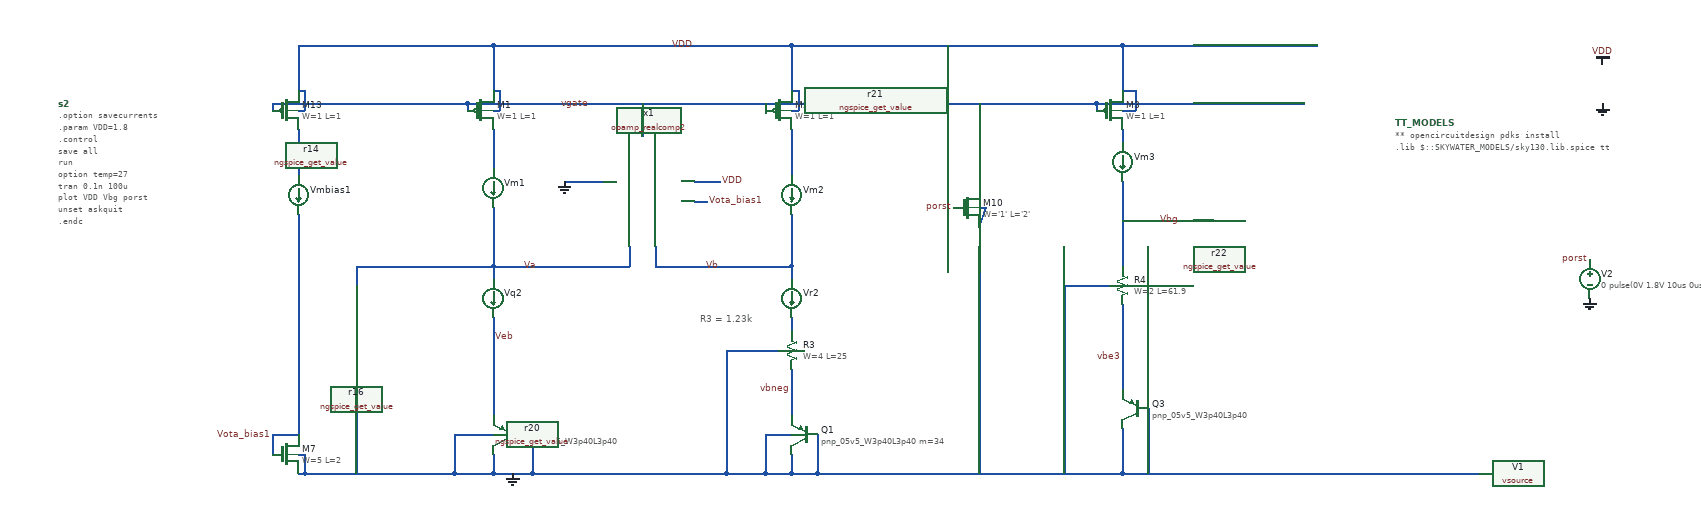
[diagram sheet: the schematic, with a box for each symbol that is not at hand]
v {xschem version=3.0.0 file_version=1.2 }
G {}
K {}
V {}
S {}
E {}
T {R3 = 1.23k} -650 -260 0 0 0.4 0.4 {}
N -970 -40 -970 -10 { lab=GND}
N -1030 -70 -970 -70 { lab=GND}
N -1030 -70 -1030 -10 { lab=GND}
N -970 -670 -750 -670 { lab=VDD}
N -510 -670 -310 -670 { lab=VDD}
N -510 -330 -510 -310 { lab=Vb}
N -510 -410 -510 -330 { lab=Vb}
N 0 -460 0 -330 { lab=Vbg}
N -510 -250 -510 -230 { lab=#net1}
N -510 -540 -510 -470 { lab=#net2}
N -510 -170 -510 -100 { lab=vbneg}
N -470 -70 -470 -10 { lab=GND}
N -510 -40 -510 -10 { lab=GND}
N -550 -70 -510 -70 { lab=GND}
N -550 -70 -550 -10 { lab=GND}
N -930 -70 -910 -70 { lab=GND}
N -910 -70 -910 -10 { lab=GND}
N -610 -200 -530 -200 { lab=GND}
N -610 -200 -610 -10 { lab=GND}
N -970 -250 -970 -100 { lab=Veb}
N -620 -330 -510 -330 { lab=Vb}
N -1270 -40 -1260 -40 { lab=GND}
N -1310 -70 -1310 -40 { lab=Vota_bias1}
N -1310 -70 -1270 -70 { lab=Vota_bias1}
N -1260 -40 -1260 -10 { lab=GND}
N -120 -670 0 -670 { lab=VDD}
N -510 -670 -510 -600 { lab=VDD}
N -120 -10 0 -10 { lab=GND}
N -970 -330 -970 -310 { lab=Va}
N -550 -580 -550 -570 { lab=vgate}
N -1010 -580 -1010 -570 { lab=vgate}
N -970 -540 -970 -480 { lab=#net3}
N -1270 -570 -1260 -570 { lab=VDD}
N -1260 -600 -1260 -570 { lab=VDD}
N -1270 -600 -1260 -600 { lab=VDD}
N -970 -570 -960 -570 { lab=VDD}
N -960 -600 -960 -570 { lab=VDD}
N -970 -600 -960 -600 { lab=VDD}
N -970 -670 -970 -600 { lab=VDD}
N -510 -570 -500 -570 { lab=VDD}
N -500 -600 -500 -570 { lab=VDD}
N -510 -600 -500 -600 { lab=VDD}
N -1230 -670 -970 -670 { lab=VDD}
N -70 -580 -40 -580 { lab=vgate}
N -1310 -580 -1310 -570 { lab=vgate}
N -1270 -670 -1270 -600 { lab=VDD}
N -1270 -350 -1270 -70 { lab=Vota_bias1}
N -970 -330 -900 -330 { lab=Va}
N -1100 -330 -970 -330 { lab=Va}
N -1030 -10 -970 -10 { lab=GND}
N -1100 -10 -1030 -10 { lab=GND}
N -1220 -10 -1100 -10 { lab=GND}
N -470 -10 -380 -10 { lab=GND}
N -510 -10 -470 -10 { lab=GND}
N -550 -10 -510 -10 { lab=GND}
N -610 -10 -550 -10 { lab=GND}
N -970 -10 -910 -10 { lab=GND}
N -910 -10 -850 -10 { lab=GND}
N 0 -270 0 -250 { lab=vbe3}
N -310 -670 -120 -670 { lab=VDD}
N -1010 -580 -790 -580 { lab=vgate}
N -790 -580 -310 -580 { lab=vgate}
N -970 -420 -970 -330 { lab=Va}
N -1270 -670 -1230 -670 { lab=VDD}
N -1260 -10 -1220 -10 { lab=GND}
N -1170 -580 -1010 -580 { lab=vgate}
N -1310 -580 -1170 -580 { lab=vgate}
N -1180 -330 -1180 -300 { lab=Va}
N -270 -670 -270 -650 { lab=VDD}
N -270 -590 -270 -580 { lab=vgate}
N -1180 -240 -1180 -10 { lab=GND}
N -1180 -330 -1100 -330 { lab=Va}
N 0 -670 300 -670 {
lab=VDD}
N 0 -10 550 -10 {
lab=GND}
N -720 -330 -620 -330 {
lab=Vb}
N -720 -360 -720 -330 {
lab=Vb}
N -900 -330 -760 -330 {
lab=Va}
N -760 -360 -760 -330 {
lab=Va}
N -740 -580 -740 -530 {
lab=vgate}
N -750 -670 -510 -670 {
lab=VDD}
N -310 -580 -70 -580 {
lab=vgate}
N -850 -10 -610 -10 {
lab=GND}
N -380 -10 -120 -10 {
lab=GND}
N -860 -460 -800 -460 {
lab=GND}
N -660 -460 -620 -460 {
lab=VDD}
N -660 -430 -640 -430 {
lab=Vota_bias1}
N 0 -250 0 -140 {
lab=vbe3}
N 0 -80 0 -10 {
lab=GND}
N 40 -110 40 -10 {
lab=GND}
N 0 -400 140 -400 {
lab=Vbg}
N -1270 -540 -1270 -470 {
lab=#net4}
N -1270 -410 -1270 -350 {
lab=Vota_bias1}
N -90 -300 -20 -300 {
lab=GND}
N -90 -300 -90 -10 {
lab=GND}
N -40 -580 280 -580 {
lab=vgate}
N -40 -580 -40 -570 {
lab=vgate}
N 0 -670 0 -600 {
lab=VDD}
N 0 -540 0 -520 {
lab=#net5}
N -1270 -10 -1260 -10 {
lab=GND}
N -0 -570 20 -570 {
lab=VDD}
N 20 -600 20 -570 {
lab=VDD}
N 0 -600 20 -600 {
lab=VDD}
N -220 -390 -220 -10 {
lab=GND}
N -220 -580 -220 -450 {
lab=vgate}
N -220 -420 -210 -420 { lab=GND}
N -220 -390 -210 -420 { lab=GND}
C {devices/code.sym} 420 -550 0 0 {name=TT_MODELS
only_toplevel=true
format="tcleval( @value )"
value="
** opencircuitdesign pdks install
.lib $::SKYWATER_MODELS/sky130.lib.spice tt

"
spice_ignore=false}
C {sky130_fd_pr/pnp_05v5.sym} -950 -70 0 1 {name=Q2
model=pnp_05v5_W3p40L3p40
spiceprefix=X
}
C {devices/gnd.sym} -940 -10 0 0 {name=l1 lab=GND}
C {devices/lab_pin.sym} -900 -330 3 0 {name=l5 lab=Va}
C {devices/lab_pin.sym} -620 -330 3 0 {name=l6 lab=Vb}
C {devices/ammeter.sym} -510 -280 0 0 {name=Vr2 current=4.3334e-06}
C {devices/ammeter.sym} -970 -450 0 0 {name=Vm1 current=1.0057e-05}
C {devices/ammeter.sym} -510 -440 0 0 {name=Vm2 current=1.0057e-05}
C {devices/ammeter.sym} 0 -490 0 0 {name=Vm3 current=1.0239e-05}
C {devices/ammeter.sym} -970 -280 0 0 {name=Vq2 current=4.3346e-06}
C {sky130_fd_pr/pnp_05v5.sym} -490 -70 0 1 {name=Q1
model="pnp_05v5_W3p40L3p40 m=34"
spiceprefix=X
}
C {devices/lab_pin.sym} -510 -140 0 0 {name=l4 lab=vbneg}
C {devices/lab_pin.sym} -970 -220 2 0 {name=l10 lab=Veb}
C {devices/lab_wire.sym} -820 -580 0 0 {name=l11 lab=vgate}
C {sky130_fd_pr/nfet_01v8_lvt.sym} -1290 -40 0 0 {name=M7
L=2
W=5
nf=1
mult=1
ad="'int((nf+1)/2) * W/nf * 0.29'" 
pd="'2*int((nf+1)/2) * (W/nf + 0.29)'"
as="'int((nf+2)/2) * W/nf * 0.29'" 
ps="'2*int((nf+2)/2) * (W/nf + 0.29)'"
nrd="'0.29 / W'" nrs="'0.29 / W'"
sa=0 sb=0 sd=0
model=nfet_01v8_lvt
spiceprefix=X
}
C {sky130_fd_pr/pfet_01v8_lvt.sym} -1290 -570 0 0 {name=M13
L=1
W=1
nf=1
mult=20
ad="'int((nf+1)/2) * W/nf * 0.29'" 
pd="'2*int((nf+1)/2) * (W/nf + 0.29)'"
as="'int((nf+2)/2) * W/nf * 0.29'" 
ps="'2*int((nf+2)/2) * (W/nf + 0.29)'"
nrd="'0.29 / W'" nrs="'0.29 / W'"
sa=0 sb=0 sd=0
model=pfet_01v8_lvt
spiceprefix=X
}
C {sky130_fd_pr/pfet_01v8_lvt.sym} -990 -570 0 0 {name=M1
L=1
W=1
nf=1
mult=32
ad="'int((nf+1)/2) * W/nf * 0.29'" 
pd="'2*int((nf+1)/2) * (W/nf + 0.29)'"
as="'int((nf+2)/2) * W/nf * 0.29'" 
ps="'2*int((nf+2)/2) * (W/nf + 0.29)'"
nrd="'0.29 / W'" nrs="'0.29 / W'"
sa=0 sb=0 sd=0
model=pfet_01v8_lvt
spiceprefix=X
}
C {sky130_fd_pr/pfet_01v8_lvt.sym} -530 -570 0 0 {name=M2
L=1
W=1
nf=1
mult=32
ad="'int((nf+1)/2) * W/nf * 0.29'" 
pd="'2*int((nf+1)/2) * (W/nf + 0.29)'"
as="'int((nf+2)/2) * W/nf * 0.29'" 
ps="'2*int((nf+2)/2) * (W/nf + 0.29)'"
nrd="'0.29 / W'" nrs="'0.29 / W'"
sa=0 sb=0 sd=0
model=pfet_01v8_lvt
spiceprefix=X
}
C {sky130_fd_pr/pfet_01v8_lvt.sym} -20 -570 0 0 {name=M3
L=1
W=1
nf=1
mult=32
ad="'int((nf+1)/2) * W/nf * 0.29'" 
pd="'2*int((nf+1)/2) * (W/nf + 0.29)'"
as="'int((nf+2)/2) * W/nf * 0.29'" 
ps="'2*int((nf+2)/2) * (W/nf + 0.29)'"
nrd="'0.29 / W'" nrs="'0.29 / W'"
sa=0 sb=0 sd=0
model=pfet_01v8_lvt
spiceprefix=X
}
C {devices/ngspice_probe.sym} -970 -330 0 0 {name=r1}
C {devices/ngspice_probe.sym} -510 -330 0 0 {name=r2}
C {devices/ngspice_probe.sym} -1270 -320 0 0 {name=r3}
C {devices/ngspice_probe.sym} -820 -580 0 0 {name=r5}
C {devices/ngspice_probe.sym} -510 -140 0 0 {name=r9}
C {devices/ngspice_get_value.sym} -1270 -440 0 0 {name=r16 node=i(@m.xm13.msky130_fd_pr__pfet_01v8_lvt[id])
descr="I="}
C {devices/ngspice_get_value.sym} -1250 -500 0 0 {name=r14 node=@m.xm13.msky130_fd_pr__pfet_01v8_lvt[gm]
descr="gm="}
C {devices/ngspice_get_value.sym} -950 -500 0 0 {name=r20 node=@m.xm1.msky130_fd_pr__pfet_01v8_lvt[gm]
descr="gm="}
C {devices/ngspice_get_value.sym} -540 -500 0 1 {name=r21 node=@m.xm2.msky130_fd_pr__pfet_01v8_lvt[gm]
descr="gm="}
C {devices/ngspice_get_value.sym} 10 -530 0 0 {name=r22 node=@m.xm3.msky130_fd_pr__pfet_01v8_lvt[gm]
descr="gm="}
C {devices/gnd.sym} -860 -460 0 0 {name=l3 lab=GND}
C {devices/lab_wire.sym} -620 -460 0 1 {name=l14 lab=VDD}
C {devices/lab_pin.sym} 0 -190 0 0 {name=l15 lab=vbe3}
C {sky130_fd_pr/pnp_05v5.sym} 20 -110 0 1 {name=Q3
model=pnp_05v5_W3p40L3p40
*model="pnp_05v5_W3p40L3p40 m=1"
spiceprefix=X
}
C {lab_wire.sym} 90 -400 0 0 {name=l8 sig_type=std_logic lab=Vbg}
C {lab_wire.sym} -660 -670 0 0 {name=l16 sig_type=std_logic lab=VDD}
C {devices/lab_pin.sym} -1310 -70 2 1 {name=l2 lab=Vota_bias1}
C {devices/lab_pin.sym} -640 -430 2 0 {name=l18 lab=Vota_bias1}
C {devices/ammeter.sym} -1270 -440 0 0 {name=Vmbias1 current=1.0057e-05}
C {sky130_fd_pr/res_high_po.sym} -510 -200 0 0 {name=R3
W=4
L=25
model=res_high_po
spiceprefix=X
mult=1}
C {sky130_fd_pr/res_high_po.sym} 0 -300 0 0 {name=R4
W=2
L=61.9
model=res_high_po
spiceprefix=X
mult=1}
C {devices/vsource.sym} 740 -610 0 0 {name=V1 net_name=true 
value="'VDD' pwl 0us 0 1us 'VDD'"
*value=1.8}
C {devices/vdd.sym} 740 -640 0 0 {name=l9 lab=VDD}
C {devices/gnd.sym} 740 -580 0 0 {name=l22 lab=GND}
C {devices/vsource.sym} 720 -310 0 0 {name=V2 net_name=true value="0 pulse(0V 1.8V 10us 0us 0us 5us)"}
C {devices/gnd.sym} 720 -280 0 0 {name=l12 lab=GND}
C {devices/lab_pin.sym} 720 -340 0 0 {name=l23 lab=porst}
C {design/opamp/opamp_realcomp2.sym} -740 -460 1 1 {name=x1}
C {sky130_fd_pr/nfet_01v8_lvt.sym} -240 -420 0 0 {name=M10
L='2'
W='1'
nf=1
mult=34
ad="'int((nf+1)/2) * W/nf * 0.29'" 
pd="'2*int((nf+1)/2) * (W/nf + 0.29)'"
as="'int((nf+2)/2) * W/nf * 0.29'" 
ps="'2*int((nf+2)/2) * (W/nf + 0.29)'"
nrd="'0.29 / W'" nrs="'0.29 / W'"
sa=0 sb=0 sd=0
model=nfet_01v8_lvt
spiceprefix=X
}
C {devices/lab_pin.sym} -260 -420 0 0 {name=l26 lab=porst}
C {devices/code_shown.sym} -1640 -580 0 0 {name=s2 
only_toplevel=true 
spice_ignore=false

value="
.option savecurrents

.param VDD=1.8
.control
save all

run
option temp=27
tran 0.1n 100u
plot VDD Vbg porst

unset askquit

.endc
"}
